VERSION 5.7 ;
  NOWIREEXTENSIONATPIN ON ;
  DIVIDERCHAR "/" ;
  BUSBITCHARS "[]" ;
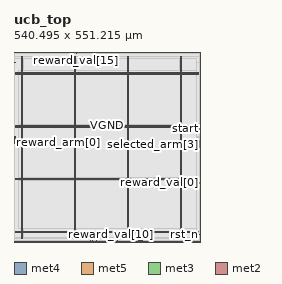
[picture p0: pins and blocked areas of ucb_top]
MACRO ucb_top
  CLASS BLOCK ;
  FOREIGN ucb_top ;
  ORIGIN 0.000 0.000 ;
  SIZE 540.495 BY 551.215 ;
  PIN VGND
    DIRECTION INOUT ;
    USE GROUND ;
    PORT
      LAYER met4 ;
        RECT 24.340 10.640 25.940 538.800 ;
    END
    PORT
      LAYER met4 ;
        RECT 177.940 10.640 179.540 538.800 ;
    END
    PORT
      LAYER met4 ;
        RECT 331.540 10.640 333.140 538.800 ;
    END
    PORT
      LAYER met4 ;
        RECT 485.140 10.640 486.740 538.800 ;
    END
    PORT
      LAYER met5 ;
        RECT 5.280 30.030 534.760 31.630 ;
    END
    PORT
      LAYER met5 ;
        RECT 5.280 183.210 534.760 184.810 ;
    END
    PORT
      LAYER met5 ;
        RECT 5.280 336.390 534.760 337.990 ;
    END
    PORT
      LAYER met5 ;
        RECT 5.280 489.570 534.760 491.170 ;
    END
  END VGND
  PIN VPWR
    DIRECTION INOUT ;
    USE POWER ;
    PORT
      LAYER met4 ;
        RECT 21.040 10.640 22.640 538.800 ;
    END
    PORT
      LAYER met4 ;
        RECT 174.640 10.640 176.240 538.800 ;
    END
    PORT
      LAYER met4 ;
        RECT 328.240 10.640 329.840 538.800 ;
    END
    PORT
      LAYER met4 ;
        RECT 481.840 10.640 483.440 538.800 ;
    END
    PORT
      LAYER met5 ;
        RECT 5.280 26.730 534.760 28.330 ;
    END
    PORT
      LAYER met5 ;
        RECT 5.280 179.910 534.760 181.510 ;
    END
    PORT
      LAYER met5 ;
        RECT 5.280 333.090 534.760 334.690 ;
    END
    PORT
      LAYER met5 ;
        RECT 5.280 486.270 534.760 487.870 ;
    END
  END VPWR
  PIN clk
    DIRECTION INPUT ;
    USE SIGNAL ;
    ANTENNAGATEAREA 1.286700 ;
    ANTENNADIFFAREA 0.434700 ;
    PORT
      LAYER met3 ;
        RECT 0.000 520.240 4.000 520.840 ;
    END
  END clk
  PIN reward_arm[0]
    DIRECTION INPUT ;
    USE SIGNAL ;
    ANTENNAGATEAREA 0.560700 ;
    ANTENNADIFFAREA 0.434700 ;
    PORT
      LAYER met3 ;
        RECT 0.000 289.040 4.000 289.640 ;
    END
  END reward_arm[0]
  PIN reward_arm[1]
    DIRECTION INPUT ;
    USE SIGNAL ;
    ANTENNAGATEAREA 0.560700 ;
    ANTENNADIFFAREA 0.434700 ;
    PORT
      LAYER met3 ;
        RECT 0.000 295.840 4.000 296.440 ;
    END
  END reward_arm[1]
  PIN reward_arm[2]
    DIRECTION INPUT ;
    USE SIGNAL ;
    ANTENNAGATEAREA 0.560700 ;
    ANTENNADIFFAREA 0.434700 ;
    PORT
      LAYER met3 ;
        RECT 0.000 292.440 4.000 293.040 ;
    END
  END reward_arm[2]
  PIN reward_arm[3]
    DIRECTION INPUT ;
    USE SIGNAL ;
    ANTENNAGATEAREA 0.631200 ;
    ANTENNADIFFAREA 0.434700 ;
    PORT
      LAYER met3 ;
        RECT 0.000 299.240 4.000 299.840 ;
    END
  END reward_arm[3]
  PIN reward_arm[4]
    DIRECTION INPUT ;
    USE SIGNAL ;
    ANTENNAGATEAREA 0.631200 ;
    ANTENNADIFFAREA 0.434700 ;
    PORT
      LAYER met3 ;
        RECT 0.000 306.040 4.000 306.640 ;
    END
  END reward_arm[4]
  PIN reward_arm[5]
    DIRECTION INPUT ;
    USE SIGNAL ;
    ANTENNAGATEAREA 0.631200 ;
    ANTENNADIFFAREA 0.434700 ;
    PORT
      LAYER met3 ;
        RECT 0.000 302.640 4.000 303.240 ;
    END
  END reward_arm[5]
  PIN reward_val[0]
    DIRECTION INPUT ;
    USE SIGNAL ;
    ANTENNAGATEAREA 0.647700 ;
    ANTENNADIFFAREA 0.434700 ;
    PORT
      LAYER met3 ;
        RECT 536.495 173.440 540.495 174.040 ;
    END
  END reward_val[0]
  PIN reward_val[10]
    DIRECTION INPUT ;
    USE SIGNAL ;
    ANTENNAGATEAREA 0.631200 ;
    ANTENNADIFFAREA 0.434700 ;
    PORT
      LAYER met2 ;
        RECT 280.230 0.000 280.510 4.000 ;
    END
  END reward_val[10]
  PIN reward_val[11]
    DIRECTION INPUT ;
    USE SIGNAL ;
    ANTENNAGATEAREA 0.631200 ;
    ANTENNADIFFAREA 0.434700 ;
    PORT
      LAYER met2 ;
        RECT 267.350 0.000 267.630 4.000 ;
    END
  END reward_val[11]
  PIN reward_val[12]
    DIRECTION INPUT ;
    USE SIGNAL ;
    ANTENNAGATEAREA 0.631200 ;
    ANTENNADIFFAREA 0.434700 ;
    PORT
      LAYER met2 ;
        RECT 238.370 0.000 238.650 4.000 ;
    END
  END reward_val[12]
  PIN reward_val[13]
    DIRECTION INPUT ;
    USE SIGNAL ;
    ANTENNAGATEAREA 0.631200 ;
    ANTENNADIFFAREA 0.434700 ;
    PORT
      LAYER met2 ;
        RECT 222.270 0.000 222.550 4.000 ;
    END
  END reward_val[13]
  PIN reward_val[14]
    DIRECTION INPUT ;
    USE SIGNAL ;
    ANTENNAGATEAREA 0.631200 ;
    ANTENNADIFFAREA 0.434700 ;
    PORT
      LAYER met2 ;
        RECT 228.710 0.000 228.990 4.000 ;
    END
  END reward_val[14]
  PIN reward_val[15]
    DIRECTION INPUT ;
    USE SIGNAL ;
    ANTENNAGATEAREA 0.593700 ;
    ANTENNADIFFAREA 0.434700 ;
    PORT
      LAYER met2 ;
        RECT 180.410 547.215 180.690 551.215 ;
    END
  END reward_val[15]
  PIN reward_val[1]
    DIRECTION INPUT ;
    USE SIGNAL ;
    ANTENNAGATEAREA 0.647700 ;
    ANTENNADIFFAREA 0.434700 ;
    PORT
      LAYER met3 ;
        RECT 536.495 170.040 540.495 170.640 ;
    END
  END reward_val[1]
  PIN reward_val[2]
    DIRECTION INPUT ;
    USE SIGNAL ;
    ANTENNAGATEAREA 0.631200 ;
    ANTENNADIFFAREA 0.434700 ;
    PORT
      LAYER met2 ;
        RECT 370.390 0.000 370.670 4.000 ;
    END
  END reward_val[2]
  PIN reward_val[3]
    DIRECTION INPUT ;
    USE SIGNAL ;
    ANTENNAGATEAREA 0.631200 ;
    ANTENNADIFFAREA 0.434700 ;
    PORT
      LAYER met2 ;
        RECT 367.170 0.000 367.450 4.000 ;
    END
  END reward_val[3]
  PIN reward_val[4]
    DIRECTION INPUT ;
    USE SIGNAL ;
    ANTENNAGATEAREA 0.560700 ;
    ANTENNADIFFAREA 0.434700 ;
    PORT
      LAYER met2 ;
        RECT 373.610 0.000 373.890 4.000 ;
    END
  END reward_val[4]
  PIN reward_val[5]
    DIRECTION INPUT ;
    USE SIGNAL ;
    ANTENNAGATEAREA 0.631200 ;
    ANTENNADIFFAREA 0.434700 ;
    PORT
      LAYER met2 ;
        RECT 363.950 0.000 364.230 4.000 ;
    END
  END reward_val[5]
  PIN reward_val[6]
    DIRECTION INPUT ;
    USE SIGNAL ;
    ANTENNAGATEAREA 0.631200 ;
    ANTENNADIFFAREA 0.434700 ;
    PORT
      LAYER met2 ;
        RECT 360.730 0.000 361.010 4.000 ;
    END
  END reward_val[6]
  PIN reward_val[7]
    DIRECTION INPUT ;
    USE SIGNAL ;
    ANTENNAGATEAREA 0.631200 ;
    ANTENNADIFFAREA 0.434700 ;
    PORT
      LAYER met2 ;
        RECT 351.070 0.000 351.350 4.000 ;
    END
  END reward_val[7]
  PIN reward_val[8]
    DIRECTION INPUT ;
    USE SIGNAL ;
    ANTENNAGATEAREA 0.631200 ;
    ANTENNADIFFAREA 0.434700 ;
    PORT
      LAYER met2 ;
        RECT 341.410 0.000 341.690 4.000 ;
    END
  END reward_val[8]
  PIN reward_val[9]
    DIRECTION INPUT ;
    USE SIGNAL ;
    ANTENNAGATEAREA 0.631200 ;
    ANTENNADIFFAREA 0.434700 ;
    PORT
      LAYER met2 ;
        RECT 299.550 0.000 299.830 4.000 ;
    END
  END reward_val[9]
  PIN reward_valid
    DIRECTION INPUT ;
    USE SIGNAL ;
    ANTENNAGATEAREA 0.593700 ;
    ANTENNADIFFAREA 0.434700 ;
    PORT
      LAYER met3 ;
        RECT 0.000 285.640 4.000 286.240 ;
    END
  END reward_valid
  PIN rst_n
    DIRECTION INPUT ;
    USE SIGNAL ;
    ANTENNAGATEAREA 0.631200 ;
    ANTENNADIFFAREA 0.434700 ;
    PORT
      LAYER met3 ;
        RECT 536.495 20.440 540.495 21.040 ;
    END
  END rst_n
  PIN selected_arm[0]
    DIRECTION OUTPUT ;
    USE SIGNAL ;
    ANTENNADIFFAREA 0.445500 ;
    PORT
      LAYER met3 ;
        RECT 536.495 275.440 540.495 276.040 ;
    END
  END selected_arm[0]
  PIN selected_arm[1]
    DIRECTION OUTPUT ;
    USE SIGNAL ;
    ANTENNADIFFAREA 0.445500 ;
    PORT
      LAYER met3 ;
        RECT 536.495 278.840 540.495 279.440 ;
    END
  END selected_arm[1]
  PIN selected_arm[2]
    DIRECTION OUTPUT ;
    USE SIGNAL ;
    ANTENNADIFFAREA 0.445500 ;
    PORT
      LAYER met3 ;
        RECT 536.495 285.640 540.495 286.240 ;
    END
  END selected_arm[2]
  PIN selected_arm[3]
    DIRECTION OUTPUT ;
    USE SIGNAL ;
    ANTENNADIFFAREA 0.445500 ;
    PORT
      LAYER met3 ;
        RECT 536.495 282.240 540.495 282.840 ;
    END
  END selected_arm[3]
  PIN selected_arm[4]
    DIRECTION OUTPUT ;
    USE SIGNAL ;
    ANTENNADIFFAREA 0.445500 ;
    PORT
      LAYER met3 ;
        RECT 536.495 292.440 540.495 293.040 ;
    END
  END selected_arm[4]
  PIN selected_arm[5]
    DIRECTION OUTPUT ;
    USE SIGNAL ;
    ANTENNADIFFAREA 0.445500 ;
    PORT
      LAYER met3 ;
        RECT 536.495 289.040 540.495 289.640 ;
    END
  END selected_arm[5]
  PIN start
    DIRECTION INPUT ;
    USE SIGNAL ;
    ANTENNAGATEAREA 0.647700 ;
    ANTENNADIFFAREA 0.434700 ;
    PORT
      LAYER met3 ;
        RECT 536.495 329.840 540.495 330.440 ;
    END
  END start
  PIN valid_out
    DIRECTION OUTPUT ;
    USE SIGNAL ;
    ANTENNADIFFAREA 0.445500 ;
    PORT
      LAYER met3 ;
        RECT 536.495 326.440 540.495 327.040 ;
    END
  END valid_out
  OBS
      LAYER nwell ;
        RECT 5.330 10.760 534.710 538.645 ;
      LAYER li1 ;
        RECT 5.520 10.795 534.520 538.645 ;
      LAYER met1 ;
        RECT 0.070 10.640 538.130 538.800 ;
      LAYER met2 ;
        RECT 0.090 546.935 180.130 547.810 ;
        RECT 180.970 546.935 538.110 547.810 ;
        RECT 0.090 4.280 538.110 546.935 ;
        RECT 0.090 4.000 221.990 4.280 ;
        RECT 222.830 4.000 228.430 4.280 ;
        RECT 229.270 4.000 238.090 4.280 ;
        RECT 238.930 4.000 267.070 4.280 ;
        RECT 267.910 4.000 279.950 4.280 ;
        RECT 280.790 4.000 299.270 4.280 ;
        RECT 300.110 4.000 341.130 4.280 ;
        RECT 341.970 4.000 350.790 4.280 ;
        RECT 351.630 4.000 360.450 4.280 ;
        RECT 361.290 4.000 363.670 4.280 ;
        RECT 364.510 4.000 366.890 4.280 ;
        RECT 367.730 4.000 370.110 4.280 ;
        RECT 370.950 4.000 373.330 4.280 ;
        RECT 374.170 4.000 538.110 4.280 ;
      LAYER met3 ;
        RECT 0.065 521.240 538.135 538.725 ;
        RECT 4.400 519.840 538.135 521.240 ;
        RECT 0.065 330.840 538.135 519.840 ;
        RECT 0.065 329.440 536.095 330.840 ;
        RECT 0.065 327.440 538.135 329.440 ;
        RECT 0.065 326.040 536.095 327.440 ;
        RECT 0.065 307.040 538.135 326.040 ;
        RECT 4.400 305.640 538.135 307.040 ;
        RECT 0.065 303.640 538.135 305.640 ;
        RECT 4.400 302.240 538.135 303.640 ;
        RECT 0.065 300.240 538.135 302.240 ;
        RECT 4.400 298.840 538.135 300.240 ;
        RECT 0.065 296.840 538.135 298.840 ;
        RECT 4.400 295.440 538.135 296.840 ;
        RECT 0.065 293.440 538.135 295.440 ;
        RECT 4.400 292.040 536.095 293.440 ;
        RECT 0.065 290.040 538.135 292.040 ;
        RECT 4.400 288.640 536.095 290.040 ;
        RECT 0.065 286.640 538.135 288.640 ;
        RECT 4.400 285.240 536.095 286.640 ;
        RECT 0.065 283.240 538.135 285.240 ;
        RECT 0.065 281.840 536.095 283.240 ;
        RECT 0.065 279.840 538.135 281.840 ;
        RECT 0.065 278.440 536.095 279.840 ;
        RECT 0.065 276.440 538.135 278.440 ;
        RECT 0.065 275.040 536.095 276.440 ;
        RECT 0.065 174.440 538.135 275.040 ;
        RECT 0.065 173.040 536.095 174.440 ;
        RECT 0.065 171.040 538.135 173.040 ;
        RECT 0.065 169.640 536.095 171.040 ;
        RECT 0.065 21.440 538.135 169.640 ;
        RECT 0.065 20.040 536.095 21.440 ;
        RECT 0.065 10.715 538.135 20.040 ;
      LAYER met4 ;
        RECT 1.215 11.735 20.640 531.585 ;
        RECT 23.040 11.735 23.940 531.585 ;
        RECT 26.340 11.735 174.240 531.585 ;
        RECT 176.640 11.735 177.540 531.585 ;
        RECT 179.940 11.735 327.840 531.585 ;
        RECT 330.240 11.735 331.140 531.585 ;
        RECT 333.540 11.735 481.440 531.585 ;
        RECT 483.840 11.735 484.740 531.585 ;
        RECT 487.140 11.735 529.130 531.585 ;
      LAYER met5 ;
        RECT 14.380 492.770 529.340 498.900 ;
        RECT 14.380 339.590 529.340 484.670 ;
        RECT 14.380 186.410 529.340 331.490 ;
        RECT 14.380 38.300 529.340 178.310 ;
  END
END ucb_top
END LIBRARY

